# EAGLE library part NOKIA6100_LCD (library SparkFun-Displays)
Nokia 6100 Color LCD Previously used in production. Spark Fun Electronics SKU : LCD-00569. Mating SMD connector : LCD-00570. SparkFun Products: 128x128 Nokia Knock-Off (Retired) Color LCD SMD connector

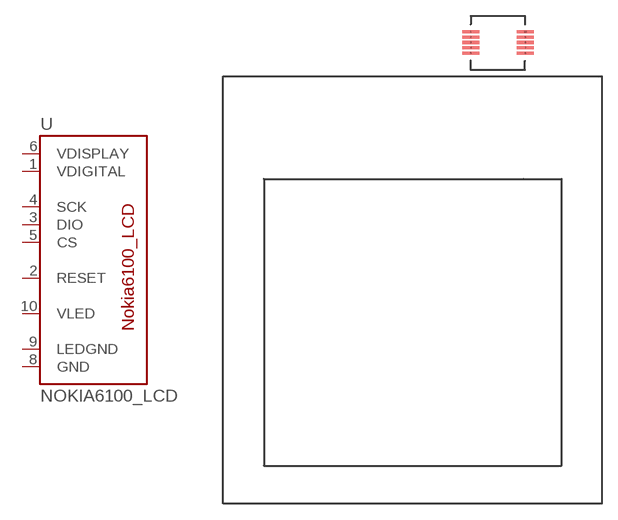
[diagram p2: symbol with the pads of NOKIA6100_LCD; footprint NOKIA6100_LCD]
Designator prefix -

## NOKIA6100_LCD  [NOKIA6100_LCD]
1  VDIGITAL
2  RESET
3  DIO
4  SCK
5  CS
6  VDISPLAY
8  GND
9  LEDGND
10  VLED

## Footprint NOKIA6100_LCD (pad centres in mm)
Nokia 6100 LED Shape and Connector For Nokia-type LCDs. Specifications: Pin count: 10 Pin pitch: " Area: Datasheet referenced for footprint: Example device(s): Retired Color LCD
smd 1.6 x 0.3: 1 24.255,44.311; 2 24.255,43.811; 3 24.255,43.311; 4 24.255,42.811; 5 24.255,42.311; 6 29.389,42.303; 7 29.389,42.803; 8 29.389,43.303; 9 29.389,43.803; 10 29.389,44.303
